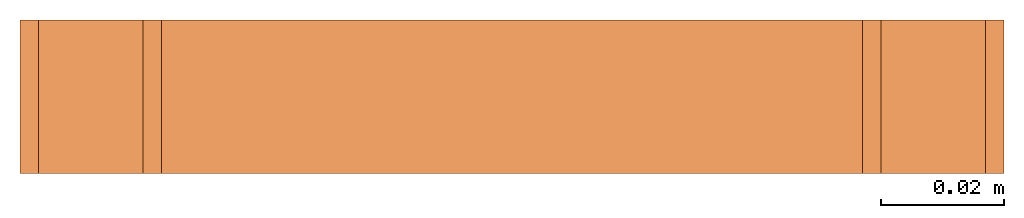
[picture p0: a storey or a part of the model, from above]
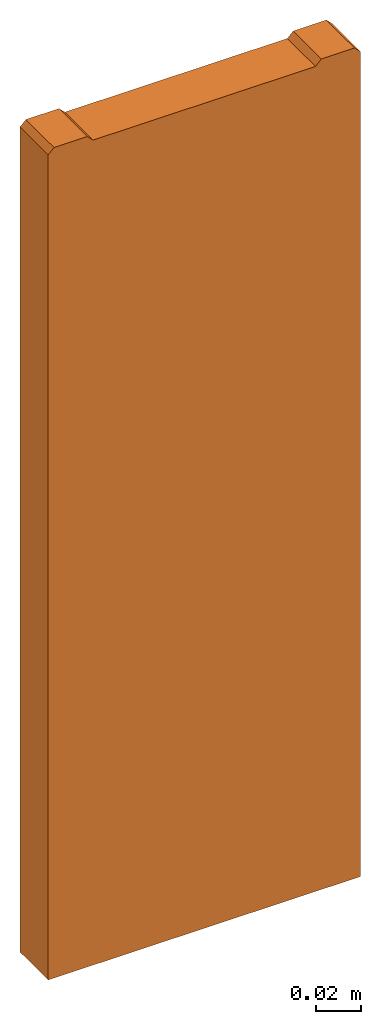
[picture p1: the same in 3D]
Properties of the parts of a building model (IFC2X3)

# File
Description: ViewDefinition [CoordinationView]
File name: 32506 - PD100 F 506 Closing endcap.ifc
Time: 2013-10-11T12:34:10
Written by: Autodesk Revit 2013
Made in: 20120221_2030(x64)

# IfcProject, Project Number
LongName: Project Name; Phase: Project Status

# IfcSite, Default
RefLatitude: 42, 21, 30, 344238; RefLongitude: -71, -3, -35, -194702; RefElevation: 0 mm

# IfcBuilding
Pset_BuildingCommon - NumberOfStoreys: 2
Other - Project Name: Project Name; Project Address: Enter address here; Project Number: Project Number; Project Issue Date: Issue Date; Client Name: Owner; Project Status: Project Status

# IfcBuildingStorey (2)
Constraints - Elevation Base: 0
Graphics - Line Weight: 1; Line Pattern: Center; Symbol: M_Level Head - Circle: M_Level Head - Circle; Symbol at End 1 Default: no; Symbol at End 2 Default: yes; Color: 0
Identity Data - Building Story: yes; Structural: no
Dimensions - Computation Height: 0 mm
Name | LongName = Name | Elevation (mm) = Constraints, Elevation (mm)
B.O. Footing | B.O. Footing | -4600
T.O. Footing | T.O. Footing | -4300

# IfcBuildingElementProxy: 32506 - PD100 F 506 Closing endcap, Civil-Drainage-Channel-ACO-RoadDrain 100:32506 - PD100 F 506 Closing endcap:32506 - PD100 F 506 Closing endcap:310733
In: B.O. Footing
Material: Acetal Resin, Black
Other - CreatedBy: www.aco.co.uk; Revision: 1
Data - ACO Hydraulic Design Software: N/A; Concrete Surround Volume - Load Class F 900 - Concrete Pavement: N/A; Channel C.S.A: N/A; Installation - Concrete Grade: N/A; Product Weight: 2.8 Kg; Connection Pipe O.D: N/A; Load Class: N/A; Hydraulic Performance: N/A; Product Standard: N/A; Product Dimensions: 25mm x 160mm x 450mm (LxWxH); Invert Depth: N/A
Constraints - Moves With Nearby Elements: no; Level: Level: T.O. Footing
Dimensions - Length: 500 mm; Custom Void Length: 0 mm; Straight Void Length: 25 mm; Volume: 1791000 mm3; Void Depth: -450 mm; Total Depth: 250 mm; I/O End Cap Void: 3650 mm; Invert Depth.: 175 mm; Straight Void Start: 0 mm
Phasing - Phase Created: Phase 1
Pset_BuildingElementProxyCommon - Reference: 32506 - PD100 F 506 Closing endcap
General - TagNumber: 0.000000; SerialNumber: 0.000000
Materials and Finishes - Access Cover/Frame Colour: N/A; Channel Material: N/A; End Cap Material: Vienite® Synthetic Resin Concrete; Access Cover/Frame Material: N/A; Channel Colour: N/A; Grating Colour: N/A; End Cap Colour: Black; Connection Pipe Material: N/A; Grating Finish: N/A; Grating Material: N/A; Access Cover/Frame Finish: N/A; Connection Pipe Colour: N/A
Identity Data - Telephone: +44 (0)1462 816666; Watermarked With: BIM Manager Premium Suite; URL: www.aco.co.uk; Assembly Code: D2040; Watermark 2: This file is water marked and users are prohibited to reproduce, adapt, distribute this information; Manufacturer: ACO Technologies plc - ACO Water Management Division; Cost: 0; Assembly Description: Rain Water Drainage; Watermarked By: www.aco.co.uk; Model: ACO RoadDrain 100 PD100F; Model Description: Monolithic Channel drainage system; Fax: +44 (0)1462 815895; Installation guidelines: http://www.aco.co.uk/download.php?id=256; Maintenance guidelines: http://www.aco.co.uk/download.php?id=256; OmniClass Number: 23.70.50.24; Type Comments: ACO RoadDrain PD100 F 506 Closing End Cap; Address: ACO Business Park, Hitchin Road, Shefford, Bedfordshire, United Kingdom SG17 5TE; Product Code: 32506; Price: POA - contact ACO; OmniClass Title: Rainwater Removal; Product brochure: http://www.aco.co.uk/download.php?id=256; e-mail Technical: technical@aco.co.uk; e-mail Sales: customersupport@aco.co.uk; Watermark 1: This file is the property of ACO Technologies PLC; Product Page URL: http://www.aco.co.uk/product_detail.php?id=21
Green Building Properties - End Cap Recyclable: Fully recyclable; Grating Recycled Material Content: N/A; Access Cover/Frame Recycled Material Content: N/A; Access Cover/Frame Recyclable: N/A; Grating Recyclable: N/A; End Cap Recycled Material Content: 20% minimum; Channel Recyclable: N/A; Channel Recycled Material Content: N/A
Construction - Closing End Cap: yes; Grating 500mm: no; 32900 - Sump Unit: no; Channel 160mm Wide: no; Inlet Outlet end cap_350 high: no; Access unit: no; Inlet Outlet end cap_450 high: no

# IfcOpeningElement: Recess (2)
In: T.O. Footing
Dimensions - Area: 30800000 mm2; Perimeter: 22200 mm; Thickness: 1550 mm; Volume: 47738200000 mm3
Constraints - Room Bounding: yes; Height Offset From Level: 0 mm; Level: Level: T.O. Footing; Related to Mass: no
Phasing - Phase Created: Phase 1
Structural - Enable Analytical Model: no; Structural: no
Materials and Finishes - Structural Material: Grass
Graphics - Coarse Scale Fill Color: 0
Analytical Properties - Thermal Resistance (R): 1.79211; Roughness: 1; Thermal mass: 2039700; Heat Transfer Coefficient (U): 0.558; Absorptance: 0.1
Construction - Default Thickness: 1550 mm; Function: 0

# IfcSlab: Floor:Generic Floor - 400mm, Floor:Generic Floor - 400mm:136436
In: T.O. Footing
PredefinedType: FLOOR; Material: Grass 50 mm, Earth 1500 mm
Dimensions - Area: 30800000 mm2; Perimeter: 22200 mm; Thickness: 1550 mm; Volume: 47738200000 mm3
Constraints - Room Bounding: yes; Height Offset From Level: 0 mm; Level: Level: T.O. Footing; Related to Mass: no
Phasing - Phase Created: Phase 1
Structural - Enable Analytical Model: no; Structural: no
Pset_SlabCommon - Reference: Generic Floor - 400mm; IsExternal: no; LoadBearing: yes
Materials and Finishes - Structural Material: Grass
Graphics - Coarse Scale Fill Color: 0
Analytical Properties - Thermal Resistance (R): 1.79211; Roughness: 1; Thermal mass: 2039700; Heat Transfer Coefficient (U): 0.558; Absorptance: 0.1
Construction - Default Thickness: 1550 mm; Function: 0
